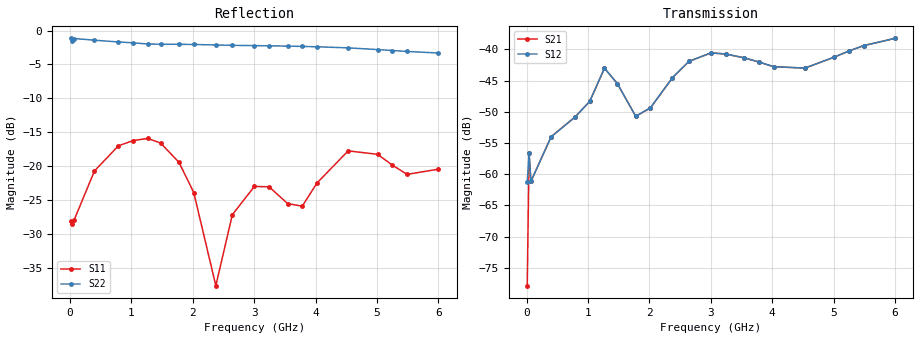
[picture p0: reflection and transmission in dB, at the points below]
!Agilent Technologies,E8364B,MY43040528,A.07.50.67
!Agilent E8364B: A.07.50.67
!Date: Sunday, September 28, 2025 21:33:28
!Correction: S11(Full 2 Port(1,2))
!S21(Full 2 Port(1,2))
!S12(Full 2 Port(1,2))
!S22(Full 2 Port(1,2))
!S2P File: Measurements: S11, S21, S12, S22:
# Hz S  dB  R 50
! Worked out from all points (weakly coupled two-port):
!   201 points, 10 MHz to 6 GHz, reference 50 ohm
!   highest |S21| = -38.24 dB at 6 GHz (marker M1); lowest = -77.9 dB at 10 MHz (marker M2)
!   lowest |S11| = -37.6 dB at 2.376 GHz (marker M3), VSWR 1.03, Z = 49.8 - j1.29 ohm
!   |S11| at or under -10 dB: start of sweep to end of sweep
!   |S22| runs from -3.3 to -1.1 dB; largest |S21 - S12| = 0.00093
!   S11 on the Smith chart (normalised r, x): 10 MHz: 1.07, -0.04; 788.7 MHz: 0.76, -0.05; 1.478 GHz: 0.89, +0.26; 6 GHz: 1.20, -0.07
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1e7  -28.11 -31.0  -77.87 136.5  -61.21 20.5  -1.15 -180.0
3.995e7  -28.48 -19.8  -56.65 17.1  -56.68 18.0  -1.55 -176.8
6.99e7  -27.87 -26.4  -61.15 14.2  -61.17 14.8  -1.17 174.4
3.9935e8  -20.69 -107.3  -54.00 4.8  -54.01 4.5  -1.42 133.5
7.887e8  -16.99 -166.4  -50.84 -44.1  -50.85 -43.8  -1.68 88.7
1.0283e9  -16.21 164.0  -48.33 -64.6  -48.33 -64.5  -1.81 61.0
1.2679e9  -15.90 133.8  -43.03 -128.2  -43.03 -128.2  -1.98 33.3
1.47755e9  -16.58 105.5  -45.48 156.3  -45.48 156.2  -2.02 9.2
1.77705e9  -19.44 65.5  -50.73 65.9  -50.72 65.6  -2.02 -26.8
2.01665e9  -23.87 31.2  -49.40 -13.0  -49.35 -12.9  -2.05 -56.3
2.37605e9  -37.60 -99.6  -44.54 -103.1  -44.53 -103.0  -2.12 -100.7
2.6456e9  -27.13 168.3  -41.92 -156.6  -41.91 -156.6  -2.18 -133.5
3.005e9  -22.97 122.0  -40.57 136.4  -40.55 136.5  -2.22 -176.1
3.2446e9  -23.03 98.6  -40.76 97.9  -40.75 98.0  -2.25 156.0
3.5441e9  -25.49 85.8  -41.36 55.9  -41.35 56.0  -2.29 121.9
3.7837e9  -25.89 99.9  -42.04 25.9  -42.02 26.0  -2.34 95.0
4.0233e9  -22.47 103.9  -42.78 -0.6  -42.77 -0.5  -2.39 68.5
4.53245e9  -17.73 65.0  -43.01 -46.9  -43.00 -46.8  -2.55 12.1
5.01165e9  -18.24 22.3  -41.25 -95.2  -41.24 -95.2  -2.80 -43.2
5.25125e9  -19.83 8.2  -40.26 -123.7  -40.26 -123.6  -2.94 -72.2
5.49085e9  -21.19 3.3  -39.40 -154.2  -39.40 -154.1  -3.08 -102.2
6e9  -20.43 -17.0  -38.24 135.8  -38.24 135.9  -3.31 -168.6
